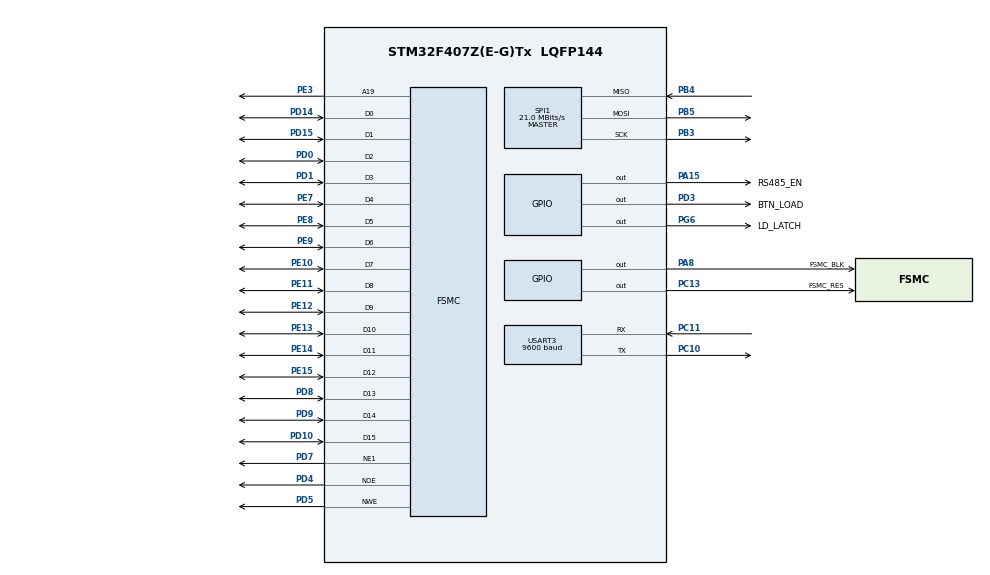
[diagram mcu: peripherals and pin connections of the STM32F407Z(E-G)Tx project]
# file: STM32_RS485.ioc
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FSMC.AddressSetupTime1=0xf
FSMC.BusTurnAroundDuration1=0
FSMC.DataSetupTime1=60
FSMC.ExtendedAddressSetupTime1=8
FSMC.ExtendedBusTurnAroundDuration1=0
FSMC.ExtendedDataSetupTime1=9
FSMC.ExtendedMode1=FSMC_EXTENDED_MODE_ENABLE
Mcu.Family=STM32F4
Mcu.Name=STM32F407Z(E-G)Tx
Mcu.Package=LQFP144
NVIC.PriorityGroup=NVIC_PRIORITYGROUP_4
NVIC.TIM2_IRQn=true\:0\:0\:false\:false\:true\:true\:true\:true
NVIC.USART3_IRQn=true\:0\:0\:false\:false\:true\:true\:true\:true
PA15.GPIO_Label=RS485_EN
PA15.Signal=GPIO_Output
PA8.GPIO_Label=FSMC_BLK
PA8.Signal=GPIO_Output
PB3.Mode=Full_Duplex_Master
PB3.Signal=SPI1_SCK
PB4.Mode=Full_Duplex_Master
PB4.Signal=SPI1_MISO
PB5.Mode=Full_Duplex_Master
PB5.Signal=SPI1_MOSI
PC10.Mode=Asynchronous
PC10.Signal=USART3_TX
PC11.Mode=Asynchronous
PC11.Signal=USART3_RX
PC13-ANTI_TAMP.GPIO_Label=FSMC_RES
PC13-ANTI_TAMP.Signal=GPIO_Output
PD0.Signal=FSMC_D2_DA2
PD1.Signal=FSMC_D3_DA3
PD10.Signal=FSMC_D15_DA15
PD14.Signal=FSMC_D0_DA0
PD15.Signal=FSMC_D1_DA1
PD3.GPIO_Label=BTN_LOAD
PD3.Signal=GPIO_Output
PD4.Signal=FSMC_NOE
PD5.Signal=FSMC_NWE
PD7.Mode=NorPsramChipSelect1_1
PD7.Signal=FSMC_NE1
PD8.Signal=FSMC_D13_DA13
PD9.Signal=FSMC_D14_DA14
PE10.Signal=FSMC_D7_DA7
PE11.Signal=FSMC_D8_DA8
PE12.Signal=FSMC_D9_DA9
PE13.Signal=FSMC_D10_DA10
PE14.Signal=FSMC_D11_DA11
PE15.Signal=FSMC_D12_DA12
PE3.Signal=FSMC_A19
PE7.Signal=FSMC_D4_DA4
PE8.Signal=FSMC_D5_DA5
PE9.Signal=FSMC_D6_DA6
PG6.GPIO_Label=LD_LATCH
PG6.Signal=GPIO_Output
ProjectManager.HeapSize=0x200
ProjectManager.StackSize=0x400
ProjectManager.TargetToolchain=STM32CubeIDE
RCC.48MHZClocksFreq_Value=84000000
RCC.AHBFreq_Value=168000000
RCC.APB1CLKDivider=RCC_HCLK_DIV4
RCC.APB1Freq_Value=42000000
RCC.APB1TimFreq_Value=84000000
RCC.APB2CLKDivider=RCC_HCLK_DIV4
RCC.APB2Freq_Value=42000000
RCC.APB2TimFreq_Value=84000000
RCC.CortexFreq_Value=168000000
RCC.HCLKFreq_Value=168000000
RCC.HSE_VALUE=25000000
RCC.HSI_VALUE=16000000
RCC.LSE_VALUE=32768
RCC.PLLM=8
RCC.PLLN=168
RCC.SYSCLKFreq_VALUE=168000000
RCC.SYSCLKSource=RCC_SYSCLKSOURCE_PLLCLK
RCC.VCOOutputFreq_Value=336000000
SH.FSMC_A19.0=FSMC_A19,A19_1
SH.FSMC_D0_DA0.0=FSMC_D0,16b-d1
SH.FSMC_D10_DA10.0=FSMC_D10,16b-d1
SH.FSMC_D11_DA11.0=FSMC_D11,16b-d1
SH.FSMC_D12_DA12.0=FSMC_D12,16b-d1
SH.FSMC_D13_DA13.0=FSMC_D13,16b-d1
SH.FSMC_D14_DA14.0=FSMC_D14,16b-d1
SH.FSMC_D15_DA15.0=FSMC_D15,16b-d1
SH.FSMC_D1_DA1.0=FSMC_D1,16b-d1
SH.FSMC_D2_DA2.0=FSMC_D2,16b-d1
SH.FSMC_D3_DA3.0=FSMC_D3,16b-d1
SH.FSMC_D4_DA4.0=FSMC_D4,16b-d1
SH.FSMC_D5_DA5.0=FSMC_D5,16b-d1
SH.FSMC_D6_DA6.0=FSMC_D6,16b-d1
SH.FSMC_D7_DA7.0=FSMC_D7,16b-d1
SH.FSMC_D8_DA8.0=FSMC_D8,16b-d1
SH.FSMC_D9_DA9.0=FSMC_D9,16b-d1
SH.FSMC_NOE.0=FSMC_NOE,Lcd1
SH.FSMC_NWE.0=FSMC_NWE,Lcd1
SPI1.CalculateBaudRate=21.0 MBits/s
SPI1.Direction=SPI_DIRECTION_2LINES
SPI1.Mode=SPI_MODE_MASTER
SPI1.VirtualType=VM_MASTER
TIM2.Prescaler=839
USART3.BaudRate=9600
USART3.VirtualMode=VM_ASYNC
VP_TIM2_VS_ClockSourceINT.Mode=Internal
board=custom

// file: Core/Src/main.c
/* USER CODE BEGIN Header */
/**
  ******************************************************************************
  * @file           : main.c
  * @brief          : Main program body
  ******************************************************************************
  * @attention
  *
  * Copyright (c) 2025 STMicroelectronics.
  * All rights reserved.
  *
  * This software is licensed under terms that can be found in the LICENSE file
  * in the root directory of this software component.
  * If no LICENSE file comes with this software, it is provided AS-IS.
  *
  ******************************************************************************
  */
/* USER CODE END Header */
#include "main.h"

/* USER CODE BEGIN Includes */
#include "fsm.h"
#include "button.h"
/* USER CODE END Includes */

SPI_HandleTypeDef hspi1;

TIM_HandleTypeDef htim2;

UART_HandleTypeDef huart3;

SRAM_HandleTypeDef hsram1;

/* USER CODE BEGIN PV */
// Cờ (flag) báo hiệu ngắt timer 10ms
volatile uint8_t timer_10ms_flag = 0;
/* USER CODE END PV */

void SystemClock_Config(void);
static void MX_GPIO_Init(void);
static void MX_FSMC_Init(void);
static void MX_SPI1_Init(void);
static void MX_TIM2_Init(void);
static void MX_USART3_UART_Init(void);

/* USER CODE BEGIN 0 */
void HAL_TIM_PeriodElapsedCallback(TIM_HandleTypeDef *htim)
{
    if (htim->Instance == TIM2) {
        timer_10ms_flag = 1; // Bật cờ
    }
}
/* USER CODE END 0 */

int main(void)
{

  /* MCU Configuration--------------------------------------------------------*/

  /* Reset of all peripherals, Initializes the Flash interface and the Systick. */
  HAL_Init();

  /* Configure the system clock */
  SystemClock_Config();

  /* Initialize all configured peripherals */
  MX_GPIO_Init();
  MX_FSMC_Init();
  MX_SPI1_Init();
  MX_TIM2_Init();
  MX_USART3_UART_Init();
  /* USER CODE BEGIN 2 */

  // Khởi tạo Máy trạng thái
    FSM_Init();

    // Bắt đầu Timer ngắt (10ms)
    HAL_TIM_Base_Start_IT(&htim2);

  /* USER CODE END 2 */

  /* Infinite loop */
  /* USER CODE BEGIN WHILE */
  while (1)
  {
	      // Tự động xóa lỗi nếu UART bị treo
	      if (__HAL_UART_GET_FLAG(&huart3, UART_FLAG_ORE)) {
	    	  __HAL_UART_CLEAR_OREFLAG(&huart3);
	      // Hoặc đọc DR: uint32_t temp = huart3.Instance->DR;
	      }
    /* USER CODE END WHILE */

    /* USER CODE BEGIN 3 */
	  // 1. Chạy logic FSM liên tục (cho chế độ AUTO và Timeout)
	      FSM_Run();

	      // 2. Xử lý các tác vụ 10ms
	      if (timer_10ms_flag == 1) {
	          timer_10ms_flag = 0; // Xóa cờ

	          button_scan(); // Quét nút nhấn
	          FSM_Button_Handle(); // Xử lý logic nút nhấn
	      }
  }
  /* USER CODE END 3 */
}

void SystemClock_Config(void)
{
  RCC_OscInitTypeDef RCC_OscInitStruct = {0};
  RCC_ClkInitTypeDef RCC_ClkInitStruct = {0};

  /** Configure the main internal regulator output voltage
  */
  __HAL_RCC_PWR_CLK_ENABLE();
  __HAL_PWR_VOLTAGESCALING_CONFIG(PWR_REGULATOR_VOLTAGE_SCALE1);

  /** Initializes the RCC Oscillators according to the specified parameters
  * in the RCC_OscInitTypeDef structure.
  */
  RCC_OscInitStruct.OscillatorType = RCC_OSCILLATORTYPE_HSI;
  RCC_OscInitStruct.HSIState = RCC_HSI_ON;
  RCC_OscInitStruct.HSICalibrationValue = RCC_HSICALIBRATION_DEFAULT;
  RCC_OscInitStruct.PLL.PLLState = RCC_PLL_ON;
  RCC_OscInitStruct.PLL.PLLSource = RCC_PLLSOURCE_HSI;
  RCC_OscInitStruct.PLL.PLLM = 8;
  RCC_OscInitStruct.PLL.PLLN = 168;
  RCC_OscInitStruct.PLL.PLLP = RCC_PLLP_DIV2;
  RCC_OscInitStruct.PLL.PLLQ = 4;
  if (HAL_RCC_OscConfig(&RCC_OscInitStruct) != HAL_OK)
  {
    Error_Handler();
  }

  /** Initializes the CPU, AHB and APB buses clocks
  */
  RCC_ClkInitStruct.ClockType = RCC_CLOCKTYPE_HCLK|RCC_CLOCKTYPE_SYSCLK
                              |RCC_CLOCKTYPE_PCLK1|RCC_CLOCKTYPE_PCLK2;
  RCC_ClkInitStruct.SYSCLKSource = RCC_SYSCLKSOURCE_PLLCLK;
  RCC_ClkInitStruct.AHBCLKDivider = RCC_SYSCLK_DIV1;
  RCC_ClkInitStruct.APB1CLKDivider = RCC_HCLK_DIV4;
  RCC_ClkInitStruct.APB2CLKDivider = RCC_HCLK_DIV2;

  if (HAL_RCC_ClockConfig(&RCC_ClkInitStruct, FLASH_LATENCY_5) != HAL_OK)
  {
    Error_Handler();
  }
}

static void MX_SPI1_Init(void)
{

  /* SPI1 parameter configuration*/
  hspi1.Instance = SPI1;
  hspi1.Init.Mode = SPI_MODE_MASTER;
  hspi1.Init.Direction = SPI_DIRECTION_2LINES_RXONLY;
  hspi1.Init.DataSize = SPI_DATASIZE_8BIT;
  hspi1.Init.CLKPolarity = SPI_POLARITY_LOW;
  hspi1.Init.CLKPhase = SPI_PHASE_1EDGE;
  hspi1.Init.NSS = SPI_NSS_SOFT;
  hspi1.Init.BaudRatePrescaler = SPI_BAUDRATEPRESCALER_2;
  hspi1.Init.FirstBit = SPI_FIRSTBIT_MSB;
  hspi1.Init.TIMode = SPI_TIMODE_DISABLE;
  hspi1.Init.CRCCalculation = SPI_CRCCALCULATION_DISABLE;
  hspi1.Init.CRCPolynomial = 10;
  if (HAL_SPI_Init(&hspi1) != HAL_OK)
  {
    Error_Handler();
  }

}

static void MX_TIM2_Init(void)
{

  TIM_ClockConfigTypeDef sClockSourceConfig = {0};
  TIM_MasterConfigTypeDef sMasterConfig = {0};

  htim2.Instance = TIM2;
  htim2.Init.Prescaler = 8399;
  htim2.Init.CounterMode = TIM_COUNTERMODE_UP;
  htim2.Init.Period = 99;
  htim2.Init.ClockDivision = TIM_CLOCKDIVISION_DIV1;
  htim2.Init.AutoReloadPreload = TIM_AUTORELOAD_PRELOAD_DISABLE;
  if (HAL_TIM_Base_Init(&htim2) != HAL_OK)
  {
    Error_Handler();
  }
  sClockSourceConfig.ClockSource = TIM_CLOCKSOURCE_INTERNAL;
  if (HAL_TIM_ConfigClockSource(&htim2, &sClockSourceConfig) != HAL_OK)
  {
    Error_Handler();
  }
  sMasterConfig.MasterOutputTrigger = TIM_TRGO_RESET;
  sMasterConfig.MasterSlaveMode = TIM_MASTERSLAVEMODE_DISABLE;
  if (HAL_TIMEx_MasterConfigSynchronization(&htim2, &sMasterConfig) != HAL_OK)
  {
    Error_Handler();
  }

}

static void MX_USART3_UART_Init(void)
{

  huart3.Instance = USART3;
  huart3.Init.BaudRate = 9600;
  huart3.Init.WordLength = UART_WORDLENGTH_8B;
  huart3.Init.StopBits = UART_STOPBITS_1;
  huart3.Init.Parity = UART_PARITY_NONE;
  huart3.Init.Mode = UART_MODE_TX_RX;
  huart3.Init.HwFlowCtl = UART_HWCONTROL_NONE;
  huart3.Init.OverSampling = UART_OVERSAMPLING_16;
  if (HAL_UART_Init(&huart3) != HAL_OK)
  {
    Error_Handler();
  }

}

static void MX_GPIO_Init(void)
{
  GPIO_InitTypeDef GPIO_InitStruct = {0};

  /* GPIO Ports Clock Enable */
  __HAL_RCC_GPIOE_CLK_ENABLE();
  __HAL_RCC_GPIOC_CLK_ENABLE();
  __HAL_RCC_GPIOD_CLK_ENABLE();
  __HAL_RCC_GPIOG_CLK_ENABLE();
  __HAL_RCC_GPIOA_CLK_ENABLE();
  __HAL_RCC_GPIOB_CLK_ENABLE();

  /*Configure GPIO pin Output Level */
  HAL_GPIO_WritePin(FSMC_RES_GPIO_Port, FSMC_RES_Pin, GPIO_PIN_RESET);

  /*Configure GPIO pin Output Level */
  HAL_GPIO_WritePin(LD_LATCH_GPIO_Port, LD_LATCH_Pin, GPIO_PIN_RESET);

  /*Configure GPIO pin Output Level */
  HAL_GPIO_WritePin(GPIOA, FSMC_BLK_Pin|RS485_EN_Pin, GPIO_PIN_RESET);

  /*Configure GPIO pin Output Level */
  HAL_GPIO_WritePin(BTN_LOAD_GPIO_Port, BTN_LOAD_Pin, GPIO_PIN_RESET);

  /*Configure GPIO pin : FSMC_RES_Pin */
  GPIO_InitStruct.Pin = FSMC_RES_Pin;
  GPIO_InitStruct.Mode = GPIO_MODE_OUTPUT_PP;
  GPIO_InitStruct.Pull = GPIO_NOPULL;
  GPIO_InitStruct.Speed = GPIO_SPEED_FREQ_LOW;
  HAL_GPIO_Init(FSMC_RES_GPIO_Port, &GPIO_InitStruct);

  /*Configure GPIO pin : LD_LATCH_Pin */
  GPIO_InitStruct.Pin = LD_LATCH_Pin;
  GPIO_InitStruct.Mode = GPIO_MODE_OUTPUT_PP;
  GPIO_InitStruct.Pull = GPIO_NOPULL;
  GPIO_InitStruct.Speed = GPIO_SPEED_FREQ_LOW;
  HAL_GPIO_Init(LD_LATCH_GPIO_Port, &GPIO_InitStruct);

  /*Configure GPIO pins : FSMC_BLK_Pin RS485_EN_Pin */
  GPIO_InitStruct.Pin = FSMC_BLK_Pin|RS485_EN_Pin;
  GPIO_InitStruct.Mode = GPIO_MODE_OUTPUT_PP;
  GPIO_InitStruct.Pull = GPIO_NOPULL;
  GPIO_InitStruct.Speed = GPIO_SPEED_FREQ_LOW;
  HAL_GPIO_Init(GPIOA, &GPIO_InitStruct);

  /*Configure GPIO pin : BTN_LOAD_Pin */
  GPIO_InitStruct.Pin = BTN_LOAD_Pin;
  GPIO_InitStruct.Mode = GPIO_MODE_OUTPUT_PP;
  GPIO_InitStruct.Pull = GPIO_NOPULL;
  GPIO_InitStruct.Speed = GPIO_SPEED_FREQ_LOW;
  HAL_GPIO_Init(BTN_LOAD_GPIO_Port, &GPIO_InitStruct);

}

/* FSMC initialization function */
static void MX_FSMC_Init(void)
{

  FSMC_NORSRAM_TimingTypeDef Timing = {0};
  FSMC_NORSRAM_TimingTypeDef ExtTiming = {0};

  /** Perform the SRAM1 memory initialization sequence
  */
  hsram1.Instance = FSMC_NORSRAM_DEVICE;
  hsram1.Extended = FSMC_NORSRAM_EXTENDED_DEVICE;
  /* hsram1.Init */
  hsram1.Init.NSBank = FSMC_NORSRAM_BANK1;
  hsram1.Init.DataAddressMux = FSMC_DATA_ADDRESS_MUX_DISABLE;
  hsram1.Init.MemoryType = FSMC_MEMORY_TYPE_SRAM;
  hsram1.Init.MemoryDataWidth = FSMC_NORSRAM_MEM_BUS_WIDTH_16;
  hsram1.Init.BurstAccessMode = FSMC_BURST_ACCESS_MODE_DISABLE;
  hsram1.Init.WaitSignalPolarity = FSMC_WAIT_SIGNAL_POLARITY_LOW;
  hsram1.Init.WrapMode = FSMC_WRAP_MODE_DISABLE;
  hsram1.Init.WaitSignalActive = FSMC_WAIT_TIMING_BEFORE_WS;
  hsram1.Init.WriteOperation = FSMC_WRITE_OPERATION_ENABLE;
  hsram1.Init.WaitSignal = FSMC_WAIT_SIGNAL_DISABLE;
  hsram1.Init.ExtendedMode = FSMC_EXTENDED_MODE_ENABLE;
  hsram1.Init.AsynchronousWait = FSMC_ASYNCHRONOUS_WAIT_DISABLE;
  hsram1.Init.WriteBurst = FSMC_WRITE_BURST_DISABLE;
  hsram1.Init.PageSize = FSMC_PAGE_SIZE_NONE;
  /* Timing */
  Timing.AddressSetupTime = 0xf;
  Timing.AddressHoldTime = 15;
  Timing.DataSetupTime = 60;
  Timing.BusTurnAroundDuration = 0;
  Timing.CLKDivision = 16;
  Timing.DataLatency = 17;
  Timing.AccessMode = FSMC_ACCESS_MODE_A;
  /* ExtTiming */
  ExtTiming.AddressSetupTime = 8;
  ExtTiming.AddressHoldTime = 15;
  ExtTiming.DataSetupTime = 9;
  ExtTiming.BusTurnAroundDuration = 0;
  ExtTiming.CLKDivision = 16;
  ExtTiming.DataLatency = 17;
  ExtTiming.AccessMode = FSMC_ACCESS_MODE_A;

  if (HAL_SRAM_Init(&hsram1, &Timing, &ExtTiming) != HAL_OK)
  {
    Error_Handler( );
  }

}

void Error_Handler(void)
{
  __disable_irq();
  while (1)
  {
  }
}
